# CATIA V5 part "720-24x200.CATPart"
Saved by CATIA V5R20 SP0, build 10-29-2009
Part number: 720-24x200
Definition: NONE
Nomenclature: 720-24x200
Source: Unknown
Description: 720-24x200
Bounding box of the stored display mesh (mm): x 0 to 200, y -12 to 12, z -12 to 12
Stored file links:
  C:\Users\Utente\Desktop\IO LAVORO\3D X SITO CF\X SITO\720\720-24x200.CATPart

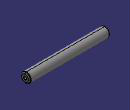
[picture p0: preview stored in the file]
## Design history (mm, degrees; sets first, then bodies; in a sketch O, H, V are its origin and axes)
Body1 "720-24x200" (main body)
  Solid1: solid without history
